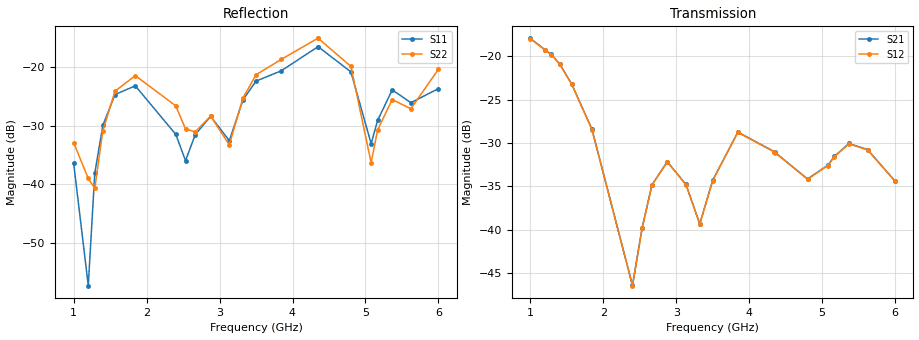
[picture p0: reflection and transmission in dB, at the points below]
!Agilent Technologies,E8364B,MY43040528,A.07.50.67
!Agilent E8364B: A.07.50.67
!Date: Sunday, March 01, 2026 16:22:02
!Correction: S11(Full 2 Port(1,2))
!S21(Full 2 Port(1,2))
!S12(Full 2 Port(1,2))
!S22(Full 2 Port(1,2))
!S2P File: Measurements: S11, S21, S12, S22:
# Hz S  dB  R 50
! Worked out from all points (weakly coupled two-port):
!   451 points, 1 GHz to 6 GHz, reference 50 ohm
!   highest |S21| = -17.93 dB at 1 GHz (marker M1); lowest = -46.4 dB at 2.4 GHz (marker M2)
!   lowest |S11| = -57.3 dB at 1.2 GHz (marker M3), VSWR 1.00, Z = 50 - j0.127 ohm
!   |S11| at or under -10 dB: start of sweep to end of sweep
!   |S22| runs from -41.8 to -15.0 dB; largest |S21 - S12| = 0.00056
!   S11 on the Smith chart (normalised r, x): 1 GHz: 1.03, +0.01; 4.356 GHz: 1.20, -0.26; 6 GHz: 0.97, -0.13
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1e9  -36.42 24.8  -17.93 27.6  -17.97 27.7  -32.89 -10.4
1.2e9  -57.31 -68.8  -19.24 -32.7  -19.27 -32.7  -38.99 11.6
1.288889e9  -38.13 -149.8  -19.79 -61.7  -19.82 -61.6  -40.68 66.0
1.4e9  -29.91 -177.1  -20.85 -99.1  -20.89 -99.0  -30.82 84.3
1.566667e9  -24.65 142.7  -23.20 -154.2  -23.23 -154.2  -24.08 49.1
1.844444e9  -23.16 87.6  -28.42 119.7  -28.45 119.8  -21.41 -13.0
2.4e9  -31.46 23.9  -46.44 -118.4  -46.47 -118.4  -26.59 -103.7
2.533333e9  -35.95 51.6  -39.76 126.0  -39.81 126.1  -30.54 -107.0
2.666667e9  -31.49 77.0  -34.84 62.8  -34.87 62.9  -31.02 -89.2
2.877778e9  -28.38 51.5  -32.16 -23.1  -32.20 -23.1  -28.33 -107.5
3.133333e9  -32.53 65.8  -34.79 -114.3  -34.83 -114.2  -33.25 -101.7
3.322222e9  -25.52 75.3  -39.34 -136.7  -39.37 -136.6  -25.19 -92.0
3.5e9  -22.35 50.8  -34.30 -153.8  -34.34 -153.7  -21.27 -123.5
3.844444e9  -20.60 21.9  -28.75 86.0  -28.79 86.1  -18.65 -170.2
4.344444e9  -16.52 -43.6  -31.00 -94.7  -31.04 -94.6  -15.05 106.0
4.355556e9  -16.52 -45.4  -31.09 -98.6  -31.13 -98.6  -15.07 103.8
4.8e9  -20.77 -118.9  -34.15 72.1  -34.19 72.1  -19.84 13.4
5.077778e9  -33.04 -99.2  -32.57 -81.9  -32.61 -81.8  -36.31 23.2
5.166667e9  -29.06 -68.5  -31.56 -127.3  -31.60 -127.2  -30.68 63.7
5.366667e9  -23.85 -88.6  -30.06 139.7  -30.10 139.7  -25.51 38.4
5.622222e9  -26.04 -114.0  -30.76 34.1  -30.81 34.1  -27.08 30.9
6e9  -23.64 -100.7  -34.40 -75.0  -34.43 -75.0  -20.33 2.8
